VERSION 5.7 ;
  NOWIREEXTENSIONATPIN ON ;
  DIVIDERCHAR "/" ;
  BUSBITCHARS "[]" ;
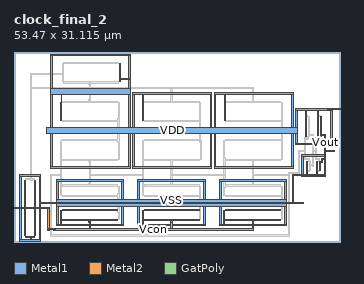
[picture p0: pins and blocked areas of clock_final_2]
MACRO clock_final_2
  CLASS BLOCK ;
  FOREIGN clock_final_2 ;
  ORIGIN 0.000 0.000 ;
  SIZE 53.470 BY 31.115 ;
  PIN VDD
    USE POWER ;
    PORT
      LAYER Metal1 ;
        RECT 6.055 30.465 19.055 30.765 ;
        RECT 6.055 25.065 6.355 30.465 ;
        RECT 17.275 26.825 17.435 29.205 ;
        RECT 18.755 26.825 19.055 30.465 ;
        RECT 17.275 26.665 19.055 26.825 ;
        RECT 17.275 26.205 17.435 26.665 ;
        RECT 18.755 25.065 19.055 26.665 ;
        RECT 6.055 24.115 19.055 25.065 ;
        RECT 6.055 18.715 6.355 24.115 ;
        RECT 7.700 22.905 7.860 24.115 ;
        RECT 7.665 19.905 7.860 22.905 ;
        RECT 18.755 18.715 19.055 24.115 ;
        RECT 19.405 24.115 32.405 24.415 ;
        RECT 19.405 18.715 19.705 24.115 ;
        RECT 21.050 19.905 21.210 24.115 ;
        RECT 32.105 18.715 32.405 24.115 ;
        RECT 32.755 24.115 45.755 24.415 ;
        RECT 32.755 18.715 33.055 24.115 ;
        RECT 34.400 19.905 34.560 24.115 ;
        RECT 45.455 18.715 45.755 24.115 ;
        RECT 46.105 21.605 52.105 21.905 ;
        RECT 46.105 18.715 46.405 21.605 ;
        RECT 5.380 17.765 46.405 18.715 ;
        RECT 5.380 17.760 45.760 17.765 ;
        RECT 6.055 12.365 6.355 17.760 ;
        RECT 18.755 12.365 19.055 17.760 ;
        RECT 6.055 12.065 19.055 12.365 ;
        RECT 19.405 12.360 19.705 17.760 ;
        RECT 32.105 12.360 32.405 17.760 ;
        RECT 19.405 12.060 32.405 12.360 ;
        RECT 32.760 12.360 33.060 17.760 ;
        RECT 45.460 12.360 45.760 17.760 ;
        RECT 46.105 16.205 46.405 17.765 ;
        RECT 47.700 17.300 47.860 21.605 ;
        RECT 49.765 17.300 49.925 21.605 ;
        RECT 51.805 16.205 52.105 21.605 ;
        RECT 46.105 15.905 52.105 16.205 ;
        RECT 32.760 12.060 45.760 12.360 ;
      LAYER Metal2 ;
        RECT 51.405 21.655 53.470 21.855 ;
    END
  END VDD
  PIN VSS
    USE GROUND ;
    PORT
      LAYER Metal1 ;
        RECT 47.075 14.000 51.075 14.300 ;
        RECT 47.075 11.100 47.375 14.000 ;
        RECT 47.925 11.100 48.085 13.255 ;
        RECT 49.555 11.100 49.715 13.255 ;
        RECT 50.775 11.100 51.075 14.000 ;
        RECT 47.075 11.030 51.075 11.100 ;
        RECT 0.900 10.730 4.400 11.030 ;
        RECT 0.900 0.330 1.200 10.730 ;
        RECT 4.100 6.485 4.400 10.730 ;
        RECT 45.605 10.870 51.075 11.030 ;
        RECT 6.910 9.870 17.910 10.170 ;
        RECT 6.910 6.970 7.210 9.870 ;
        RECT 17.610 6.970 17.910 9.870 ;
        RECT 20.295 9.870 31.295 10.170 ;
        RECT 20.295 6.970 20.595 9.870 ;
        RECT 30.995 6.970 31.295 9.870 ;
        RECT 33.635 9.870 44.635 10.170 ;
        RECT 33.635 6.970 33.935 9.870 ;
        RECT 44.335 6.970 44.635 9.870 ;
        RECT 6.910 6.485 44.635 6.970 ;
        RECT 45.605 6.505 45.765 10.870 ;
        RECT 47.075 10.800 51.075 10.870 ;
        RECT 4.100 6.480 44.635 6.485 ;
        RECT 45.540 6.480 45.830 6.505 ;
        RECT 4.100 6.325 45.830 6.480 ;
        RECT 1.895 0.780 3.395 0.940 ;
        RECT 2.765 0.330 2.925 0.780 ;
        RECT 4.100 0.330 4.400 6.325 ;
        RECT 6.910 6.320 45.830 6.325 ;
        RECT 6.910 5.840 44.635 6.320 ;
        RECT 45.540 6.295 45.830 6.320 ;
        RECT 6.910 2.940 7.210 5.840 ;
        RECT 7.665 2.940 7.825 5.125 ;
        RECT 17.610 2.940 17.910 5.840 ;
        RECT 6.910 2.640 17.910 2.940 ;
        RECT 20.295 2.940 20.595 5.840 ;
        RECT 21.050 2.940 21.210 5.125 ;
        RECT 30.995 2.940 31.295 5.840 ;
        RECT 20.295 2.640 31.295 2.940 ;
        RECT 33.635 2.940 33.935 5.840 ;
        RECT 34.390 2.940 34.550 5.125 ;
        RECT 44.335 2.940 44.635 5.840 ;
        RECT 33.635 2.640 44.635 2.940 ;
        RECT 0.900 0.030 4.400 0.330 ;
      LAYER Metal2 ;
        RECT 45.540 6.300 47.355 6.500 ;
    END
  END VSS
  PIN Vcon
    ANTENNAGATEAREA 54.000000 ;
    PORT
      LAYER GatPoly ;
        RECT 1.715 5.725 1.895 10.050 ;
        RECT 1.470 5.425 1.895 5.725 ;
        RECT 1.715 1.050 1.895 5.425 ;
        RECT 3.395 1.050 3.575 10.050 ;
        RECT 7.935 5.125 16.935 5.305 ;
        RECT 21.320 5.125 30.320 5.305 ;
        RECT 34.660 5.125 43.660 5.305 ;
        RECT 7.935 3.445 16.935 3.625 ;
        RECT 21.320 3.445 30.320 3.625 ;
        RECT 34.660 3.445 43.660 3.625 ;
        RECT 12.255 3.145 12.555 3.445 ;
        RECT 25.645 3.145 25.945 3.445 ;
        RECT 38.985 3.145 39.285 3.445 ;
      LAYER Metal1 ;
        RECT 1.475 5.470 1.765 5.680 ;
        RECT 12.300 3.150 12.510 3.440 ;
        RECT 25.690 3.150 25.900 3.440 ;
        RECT 39.030 3.150 39.240 3.440 ;
        RECT 5.495 2.145 5.785 2.170 ;
        RECT 6.525 2.145 6.815 2.170 ;
        RECT 5.495 1.985 6.815 2.145 ;
        RECT 5.495 1.960 5.785 1.985 ;
        RECT 6.525 1.960 6.815 1.985 ;
      LAYER Metal2 ;
        RECT 0.000 5.475 5.740 5.675 ;
        RECT 5.540 2.165 5.740 5.475 ;
        RECT 12.305 2.165 12.505 3.440 ;
        RECT 25.695 2.165 25.895 3.440 ;
        RECT 39.035 2.165 39.235 3.440 ;
        RECT 5.495 1.965 5.785 2.165 ;
        RECT 6.525 1.965 39.235 2.165 ;
    END
  END Vcon
  PIN Vout
    ANTENNADIFFAREA 1.598000 ;
    PORT
      LAYER Metal1 ;
        RECT 50.275 17.530 50.435 20.500 ;
        RECT 50.875 17.530 51.085 17.595 ;
        RECT 50.275 17.370 51.085 17.530 ;
        RECT 50.275 17.300 50.435 17.370 ;
        RECT 50.875 17.305 51.085 17.370 ;
        RECT 50.385 13.440 50.595 13.730 ;
        RECT 50.065 13.185 50.225 13.255 ;
        RECT 50.410 13.185 50.570 13.440 ;
        RECT 50.065 13.025 50.570 13.185 ;
        RECT 50.065 11.755 50.225 13.025 ;
      LAYER Metal2 ;
        RECT 50.880 15.010 51.080 17.595 ;
        RECT 50.880 14.810 52.530 15.010 ;
        RECT 50.390 13.685 50.590 13.730 ;
        RECT 50.880 13.685 51.080 14.810 ;
        RECT 50.390 13.485 51.080 13.685 ;
        RECT 50.390 13.440 50.590 13.485 ;
    END
  END Vout
  OBS
      LAYER GatPoly ;
        RECT 8.165 29.205 17.165 29.385 ;
        RECT 8.165 26.025 17.165 26.205 ;
        RECT 12.245 25.760 12.545 26.025 ;
        RECT 12.245 23.085 12.545 23.330 ;
        RECT 25.645 23.085 25.945 23.330 ;
        RECT 38.980 23.085 39.280 23.330 ;
        RECT 7.935 22.905 16.935 23.085 ;
        RECT 21.320 22.905 30.320 23.085 ;
        RECT 34.670 22.905 43.670 23.085 ;
        RECT 47.970 20.500 48.100 20.680 ;
        RECT 50.035 20.500 50.165 20.680 ;
        RECT 7.935 19.725 16.935 19.905 ;
        RECT 21.320 19.725 30.320 19.905 ;
        RECT 34.670 19.725 43.670 19.905 ;
        RECT 47.970 17.120 48.100 17.300 ;
        RECT 50.035 17.120 50.165 17.300 ;
        RECT 47.885 16.820 48.185 17.120 ;
        RECT 49.950 16.820 50.250 17.120 ;
        RECT 7.935 16.570 16.935 16.750 ;
        RECT 21.370 16.565 30.370 16.745 ;
        RECT 34.660 16.565 43.660 16.745 ;
        RECT 7.935 13.390 16.935 13.570 ;
        RECT 12.245 13.145 12.545 13.390 ;
        RECT 21.370 13.385 30.370 13.565 ;
        RECT 34.660 13.385 43.660 13.565 ;
        RECT 48.110 13.435 48.410 13.735 ;
        RECT 49.745 13.435 50.045 13.735 ;
        RECT 25.645 13.140 25.945 13.385 ;
        RECT 38.980 13.085 39.280 13.385 ;
        RECT 48.195 13.255 48.325 13.435 ;
        RECT 49.825 13.255 49.955 13.435 ;
        RECT 48.195 11.575 48.325 11.755 ;
        RECT 49.825 11.575 49.955 11.755 ;
        RECT 12.245 9.335 12.545 9.630 ;
        RECT 25.645 9.335 25.945 9.630 ;
        RECT 38.980 9.335 39.280 9.630 ;
        RECT 7.935 9.155 16.935 9.335 ;
        RECT 21.320 9.155 30.320 9.335 ;
        RECT 34.660 9.155 43.660 9.335 ;
        RECT 7.935 7.475 16.935 7.655 ;
        RECT 21.320 7.475 30.320 7.655 ;
        RECT 34.660 7.475 43.660 7.655 ;
      LAYER Metal1 ;
        RECT 7.895 27.660 8.055 29.205 ;
        RECT 7.870 27.370 8.080 27.660 ;
        RECT 7.895 26.205 8.055 27.370 ;
        RECT 12.290 25.765 12.500 26.055 ;
        RECT 12.290 23.035 12.500 23.325 ;
        RECT 25.690 23.035 25.900 23.325 ;
        RECT 39.025 23.035 39.235 23.325 ;
        RECT 17.045 20.200 17.205 22.905 ;
        RECT 30.430 20.200 30.590 22.905 ;
        RECT 43.780 20.200 43.940 22.905 ;
        RECT 17.020 19.910 17.230 20.200 ;
        RECT 30.405 19.910 30.615 20.200 ;
        RECT 43.755 19.910 43.965 20.200 ;
        RECT 17.045 19.905 17.205 19.910 ;
        RECT 30.430 19.905 30.590 19.910 ;
        RECT 43.780 19.905 43.940 19.910 ;
        RECT 48.210 17.530 48.370 20.500 ;
        RECT 48.845 17.530 49.055 17.595 ;
        RECT 48.210 17.370 49.055 17.530 ;
        RECT 48.210 17.300 48.370 17.370 ;
        RECT 48.845 17.305 49.055 17.370 ;
        RECT 47.930 16.825 48.140 17.115 ;
        RECT 49.995 16.825 50.205 17.115 ;
        RECT 7.665 13.865 7.825 16.570 ;
        RECT 17.045 16.565 17.205 16.570 ;
        RECT 17.020 16.275 17.230 16.565 ;
        RECT 7.640 13.575 7.850 13.865 ;
        RECT 7.665 13.570 7.825 13.575 ;
        RECT 17.045 13.570 17.205 16.275 ;
        RECT 21.100 13.860 21.260 16.565 ;
        RECT 30.480 16.560 30.640 16.565 ;
        RECT 30.405 16.270 30.640 16.560 ;
        RECT 21.025 13.570 21.260 13.860 ;
        RECT 21.100 13.565 21.260 13.570 ;
        RECT 30.480 13.565 30.640 16.270 ;
        RECT 34.390 13.860 34.550 16.565 ;
        RECT 43.770 16.555 43.930 16.565 ;
        RECT 43.745 16.265 43.955 16.555 ;
        RECT 34.365 13.570 34.575 13.860 ;
        RECT 34.390 13.565 34.550 13.570 ;
        RECT 43.770 13.565 43.930 16.265 ;
        RECT 48.155 13.440 48.365 13.730 ;
        RECT 49.790 13.440 50.000 13.730 ;
        RECT 12.290 13.150 12.500 13.440 ;
        RECT 25.690 13.145 25.900 13.435 ;
        RECT 39.025 13.090 39.235 13.380 ;
        RECT 48.435 12.615 48.595 13.255 ;
        RECT 48.840 12.615 49.050 12.680 ;
        RECT 48.435 12.455 49.050 12.615 ;
        RECT 48.435 11.755 48.595 12.455 ;
        RECT 48.840 12.390 49.050 12.455 ;
        RECT 2.700 10.320 2.990 10.345 ;
        RECT 1.895 10.160 3.395 10.320 ;
        RECT 2.700 10.135 2.990 10.160 ;
        RECT 12.290 9.335 12.500 9.625 ;
        RECT 25.690 9.335 25.900 9.625 ;
        RECT 39.025 9.335 39.235 9.625 ;
        RECT 7.665 9.150 7.825 9.155 ;
        RECT 7.640 8.860 7.850 9.150 ;
        RECT 7.665 7.655 7.825 8.860 ;
        RECT 17.045 7.950 17.205 9.155 ;
        RECT 21.050 9.150 21.210 9.155 ;
        RECT 21.025 8.860 21.235 9.150 ;
        RECT 17.020 7.660 17.230 7.950 ;
        RECT 17.045 7.655 17.205 7.660 ;
        RECT 21.050 7.655 21.210 8.860 ;
        RECT 30.430 7.950 30.590 9.155 ;
        RECT 34.390 9.150 34.550 9.155 ;
        RECT 34.365 8.860 34.575 9.150 ;
        RECT 30.405 7.660 30.615 7.950 ;
        RECT 30.430 7.655 30.590 7.660 ;
        RECT 34.390 7.655 34.550 8.860 ;
        RECT 43.770 7.950 43.930 9.155 ;
        RECT 43.745 7.660 43.955 7.950 ;
        RECT 43.770 7.655 43.930 7.660 ;
        RECT 17.045 5.120 17.205 5.125 ;
        RECT 30.430 5.120 30.590 5.125 ;
        RECT 43.770 5.120 43.930 5.125 ;
        RECT 17.020 4.830 17.230 5.120 ;
        RECT 30.405 4.830 30.615 5.120 ;
        RECT 43.745 4.830 43.955 5.120 ;
        RECT 17.045 3.625 17.205 4.830 ;
        RECT 30.430 3.625 30.590 4.830 ;
        RECT 43.770 3.625 43.930 4.830 ;
      LAYER Metal2 ;
        RECT 7.875 27.615 8.075 27.660 ;
        RECT 2.745 27.415 8.075 27.615 ;
        RECT 2.745 25.335 2.945 27.415 ;
        RECT 7.875 27.370 8.075 27.415 ;
        RECT 12.295 25.335 12.495 26.055 ;
        RECT 2.745 25.135 39.230 25.335 ;
        RECT 2.745 10.340 2.945 25.135 ;
        RECT 12.295 23.035 12.495 25.135 ;
        RECT 25.695 23.035 25.895 25.135 ;
        RECT 39.030 23.035 39.230 25.135 ;
        RECT 17.025 16.275 17.225 20.200 ;
        RECT 30.410 16.270 30.610 20.200 ;
        RECT 43.760 16.555 43.960 20.200 ;
        RECT 43.750 16.265 43.960 16.555 ;
        RECT 7.645 11.060 7.845 13.865 ;
        RECT 6.005 10.860 7.845 11.060 ;
        RECT 2.700 10.140 2.990 10.340 ;
        RECT 6.005 1.150 6.205 10.860 ;
        RECT 7.645 8.860 7.845 10.860 ;
        RECT 12.295 11.060 12.495 13.440 ;
        RECT 21.030 11.060 21.230 13.860 ;
        RECT 12.295 10.860 21.230 11.060 ;
        RECT 12.295 9.335 12.495 10.860 ;
        RECT 21.030 8.860 21.230 10.860 ;
        RECT 25.695 11.060 25.895 13.435 ;
        RECT 34.370 11.060 34.570 13.860 ;
        RECT 25.695 10.860 34.570 11.060 ;
        RECT 25.695 9.335 25.895 10.860 ;
        RECT 34.370 8.860 34.570 10.860 ;
        RECT 39.030 11.060 39.230 13.380 ;
        RECT 45.460 12.060 45.760 18.060 ;
        RECT 48.845 17.305 49.050 17.595 ;
        RECT 47.935 17.070 48.135 17.115 ;
        RECT 47.495 16.870 48.135 17.070 ;
        RECT 47.495 15.045 47.695 16.870 ;
        RECT 47.935 16.825 48.135 16.870 ;
        RECT 46.515 14.845 47.695 15.045 ;
        RECT 46.515 11.375 46.715 14.845 ;
        RECT 47.495 13.685 47.695 14.845 ;
        RECT 48.845 15.050 49.045 17.305 ;
        RECT 50.000 17.070 50.200 17.115 ;
        RECT 49.370 16.870 50.200 17.070 ;
        RECT 49.370 15.050 49.570 16.870 ;
        RECT 50.000 16.825 50.200 16.870 ;
        RECT 48.845 14.850 49.570 15.050 ;
        RECT 48.160 13.685 48.360 13.730 ;
        RECT 47.495 13.485 48.360 13.685 ;
        RECT 48.160 13.440 48.360 13.485 ;
        RECT 48.845 12.390 49.045 14.850 ;
        RECT 49.370 13.685 49.570 14.850 ;
        RECT 49.795 13.685 49.995 13.730 ;
        RECT 49.370 13.485 49.995 13.685 ;
        RECT 49.795 13.440 49.995 13.485 ;
        RECT 44.965 11.175 46.715 11.375 ;
        RECT 44.965 11.060 45.165 11.175 ;
        RECT 39.030 10.860 45.165 11.060 ;
        RECT 39.030 9.335 39.230 10.860 ;
        RECT 17.025 4.830 17.225 7.950 ;
        RECT 30.410 4.830 30.610 7.950 ;
        RECT 43.750 4.830 43.950 7.950 ;
        RECT 44.965 1.150 45.165 10.860 ;
        RECT 6.005 0.950 45.165 1.150 ;
  END
END clock_final_2
END LIBRARY

